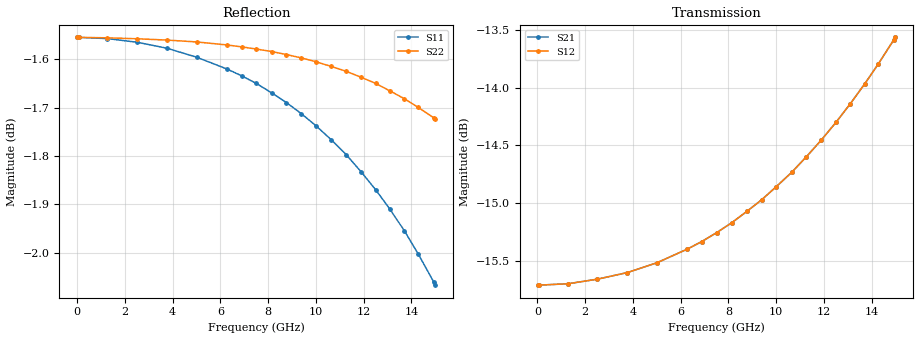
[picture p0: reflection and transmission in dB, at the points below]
!version-1
!date-03.2021
# MHz S RI R 50
!Freq ReS11 ImS11 ReS21 ImS21 ReS12 ImS12 ReS22 ImS22
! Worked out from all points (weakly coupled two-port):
!   751 points, 10 MHz to 15 GHz, reference 50 ohm
!   highest |S21| = -13.56 dB at 15 GHz (marker M1); lowest = -15.7 dB at 10 MHz (marker M2)
!   lowest |S11| = -2.1 dB at 15 GHz (marker M3), VSWR 8.44, Z = 275 - j199 ohm
!   |S11| at or under -10 dB: nowhere
!   |S22| runs from -1.7 to -1.6 dB; largest |S21 - S12| = 0
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10  0.8361 -7.82e-05  0.1639 1.91e-05  0.1639 1.91e-05  0.8361 -0.00018
70  0.8361 -0.000547  0.1639 0.000134  0.1639 0.000134  0.8361 -0.00126
1270  0.8358 -0.00994  0.1641 0.00243  0.1641 0.00243  0.8357 -0.0229
2510  0.8349 -0.0197  0.1648 0.00483  0.1648 0.00483  0.8346 -0.0452
3770  0.8334 -0.0298  0.1658 0.00734  0.1658 0.00734  0.8328 -0.0679
5010  0.8312 -0.0399  0.1673 0.00991  0.1673 0.00991  0.8303 -0.0903
6270  0.8283 -0.0505  0.1694 0.0126  0.1694 0.0126  0.8269 -0.1131
6890  0.8266 -0.0559  0.1706 0.014  0.1706 0.014  0.8249 -0.1243
7510  0.8247 -0.0613  0.172 0.0155  0.172 0.0155  0.8227 -0.1355
8150  0.8224 -0.067  0.1736 0.017  0.1736 0.017  0.8202 -0.1471
8770  0.82 -0.0727  0.1754 0.0185  0.1754 0.0185  0.8175 -0.1583
9390  0.8173 -0.0785  0.1773 0.02  0.1773 0.02  0.8146 -0.1694
10010  0.8143 -0.0844  0.1795 0.0216  0.1795 0.0216  0.8114 -0.1806
10650  0.8109 -0.0906  0.1819 0.0232  0.1819 0.0232  0.8078 -0.1921
11270  0.8073 -0.0968  0.1846 0.0248  0.1846 0.0248  0.8041 -0.2032
11890  0.8032 -0.1031  0.1875 0.0265  0.1875 0.0265  0.8 -0.2143
12510  0.7988 -0.1096  0.1907 0.0281  0.1907 0.0281  0.7957 -0.2253
13110  0.7941 -0.116  0.1941 0.0297  0.1941 0.0297  0.7911 -0.2358
13710  0.789 -0.1225  0.1978 0.0313  0.1978 0.0313  0.7863 -0.2463
14290  0.7835 -0.129  0.2017 0.0328  0.2017 0.0328  0.7813 -0.2563
14930  0.777 -0.1362  0.2064 0.0345  0.2064 0.0345  0.7755 -0.2673
15000  0.7762 -0.137  0.2069 0.0346  0.2069 0.0346  0.7748 -0.2685
